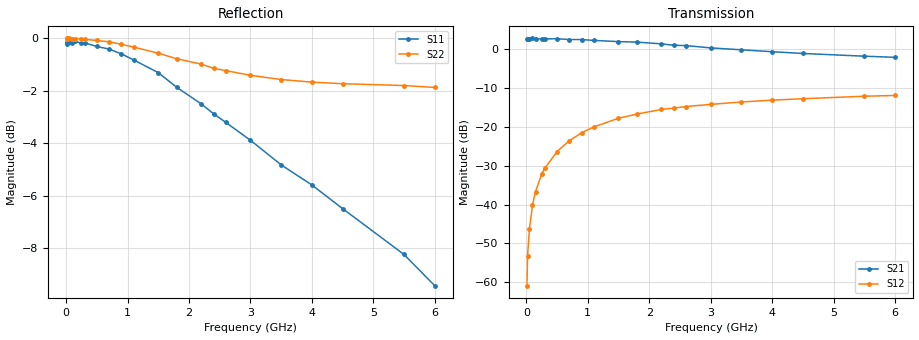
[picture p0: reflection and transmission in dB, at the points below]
! SIEMENS Discrete & RF Semiconductors
! BFY180
! Si NPN RF Bipolar Junction Transistor in MICRO-X
! VCE = 2.5 V  IC = 0.4 mA
! Common Emitter S-Parameters:  May  1997
# GHz  S  MA  R  50
!  f  S11  S21  S12  S22
! GHz  MAG  ANG  MAG  ANG  MAG  ANG  MAG  ANG
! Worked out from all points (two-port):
!   36 points, 10 MHz to 6 GHz, reference 50 ohm
!   highest |S21| = 2.84 dB at 100 MHz (marker M1); lowest = -2.0 dB at 6 GHz (marker M2)
!   |S21| within 3 dB of the highest: start of sweep to 3.554 GHz
!   lowest |S11| = -9.4 dB at 6 GHz (marker M3), VSWR 2.02, Z = 28.3 - j16.1 ohm
!   |S11| at or under -10 dB: nowhere
!   |S22| runs from -1.9 to 0.0 dB; largest |S21 - S12| = 1.4
!   S11 on the Smith chart (normalised r, x): 10 MHz: open; 700 MHz: 0.67, -5.21; 1.5 GHz: 0.51, -2.36; 2.4 GHz: 0.51, -1.38; 4 GHz: 0.52, -0.75; 6 GHz: 0.57, -0.32
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0.01  0.9838 -0.1  1.373 179.8  0.0009 88.5  0.9989 -0.2
0.02  0.9748 -0.7  1.38 179.2  0.0022 92.2  0.9999 -0.5
0.05  0.9839 -1.3  1.381 178.2  0.0048 83.1  0.9995 -1.1
0.1  0.9817 -3.1  1.387 176.3  0.0099 88.9  0.9986 -2.2
0.15  0.9865 -4.8  1.378 174.3  0.0147 86.5  0.9992 -3.3
0.25  0.9787 -8.0  1.359 170.4  0.0248 83.8  0.9987 -5.5
0.3  0.9803 -9.1  1.366 167.8  0.0293 82.5  0.9955 -6.6
0.5  0.965 -15.6  1.372 159.7  0.0482 77.9  0.9908 -11.0
0.7  0.9539 -21.4  1.338 152.4  0.0665 72.7  0.9845 -15.3
0.9  0.934 -27.2  1.337 144.6  0.0842 67.9  0.9742 -19.5
1.1  0.9096 -33.0  1.306 137.4  0.1002 63.3  0.9624 -23.6
1.5  0.8603 -44.3  1.259 122.9  0.1295 54.7  0.9369 -31.6
1.8  0.8067 -52.7  1.241 112.1  0.1468 48.8  0.9144 -37.0
2.2  0.7501 -62.3  1.178 98.8  0.1681 41.3  0.893 -44.0
2.4  0.7184 -67.1  1.131 92.7  0.175 38.2  0.8768 -47.3
2.6  0.6915 -71.4  1.119 86.7  0.1834 35.2  0.8679 -50.1
3  0.6394 -79.5  1.046 76.0  0.1956 29.5  0.8502 -56.1
3.5  0.5741 -88.2  0.988 63.0  0.2099 23.6  0.8347 -62.8
4  0.5256 -96.7  0.933 51.6  0.2217 17.9  0.8252 -69.6
4.5  0.4738 -104.6  0.886 41.2  0.2313 12.8  0.8195 -76.5
5.5  0.3874 -121.8  0.817 21.7  0.249 2.9  0.813 -90.4
6  0.3378 -131.8  0.79 13.2  0.2548 -2.1  0.8062 -97.5
